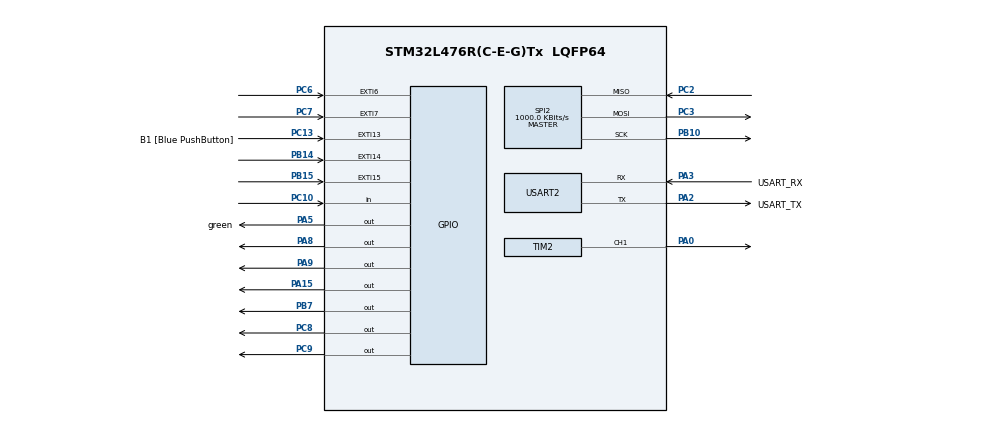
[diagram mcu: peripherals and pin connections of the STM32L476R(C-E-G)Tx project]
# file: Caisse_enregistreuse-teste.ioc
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Mcu.Family=STM32L4
Mcu.Name=STM32L476R(C-E-G)Tx
Mcu.Package=LQFP64
NVIC.PriorityGroup=NVIC_PRIORITYGROUP_4
NVIC.USART2_IRQn=true\:0\:0\:false\:false\:true\:true\:true\:true
PA0.Signal=S_TIM2_CH1
PA13\ (JTMS-SWDIO).GPIO_Label=TMS
PA13\ (JTMS-SWDIO).Mode=Serial_Wire
PA13\ (JTMS-SWDIO).Signal=SYS_JTMS-SWDIO
PA14\ (JTCK-SWCLK).GPIO_Label=TCK
PA14\ (JTCK-SWCLK).Mode=Serial_Wire
PA14\ (JTCK-SWCLK).Signal=SYS_JTCK-SWCLK
PA15\ (JTDI).GPIO_PuPd=GPIO_NOPULL
PA15\ (JTDI).GPIO_Speed=GPIO_SPEED_FREQ_HIGH
PA15\ (JTDI).Signal=GPIO_Output
PA2.GPIO_Label=USART_TX
PA2.GPIO_Mode=GPIO_MODE_AF_PP
PA2.GPIO_PuPd=GPIO_NOPULL
PA2.GPIO_Speed=GPIO_SPEED_FREQ_VERY_HIGH
PA2.Mode=Asynchronous
PA2.Signal=USART2_TX
PA3.GPIO_Label=USART_RX
PA3.GPIO_Mode=GPIO_MODE_AF_PP
PA3.GPIO_PuPd=GPIO_NOPULL
PA3.GPIO_Speed=GPIO_SPEED_FREQ_VERY_HIGH
PA3.Mode=Asynchronous
PA3.Signal=USART2_RX
PA5.GPIO_Label=green
PA5.GPIO_ModeDefaultOutputPP=GPIO_MODE_OUTPUT_PP
PA5.GPIO_PuPd=GPIO_NOPULL
PA5.GPIO_Speed=GPIO_SPEED_FREQ_LOW
PA5.Signal=GPIO_Output
PA8.Signal=GPIO_Output
PA9.Signal=GPIO_Output
PB10.Mode=Full_Duplex_Master
PB10.Signal=SPI2_SCK
PB14.GPIO_ModeDefaultEXTI=GPIO_MODE_IT_FALLING
PB14.GPIO_PuPd=GPIO_PULLUP
PB14.Signal=GPXTI14
PB15.GPIO_ModeDefaultEXTI=GPIO_MODE_IT_FALLING
PB15.GPIO_PuPd=GPIO_PULLUP
PB15.Signal=GPXTI15
PB7.GPIO_Speed=GPIO_SPEED_FREQ_HIGH
PB7.Signal=GPIO_Output
PC10.GPIO_PuPd=GPIO_PULLUP
PC10.Signal=GPIO_Input
PC13.GPIO_Label=B1 [Blue PushButton]
PC13.GPIO_ModeDefaultEXTI=GPIO_MODE_IT_FALLING
PC13.GPIO_PuPd=GPIO_PULLUP
PC13.Signal=GPXTI13
PC14-OSC32_IN\ (PC14).Mode=LSE-External-Oscillator
PC14-OSC32_IN\ (PC14).Signal=RCC_OSC32_IN
PC15-OSC32_OUT\ (PC15).Mode=LSE-External-Oscillator
PC15-OSC32_OUT\ (PC15).Signal=RCC_OSC32_OUT
PC2.Mode=Full_Duplex_Master
PC2.Signal=SPI2_MISO
PC3.Mode=Full_Duplex_Master
PC3.Signal=SPI2_MOSI
PC6.GPIO_ModeDefaultEXTI=GPIO_MODE_IT_FALLING
PC6.GPIO_PuPd=GPIO_PULLUP
PC6.Signal=GPXTI6
PC7.GPIO_ModeDefaultEXTI=GPIO_MODE_IT_FALLING
PC7.GPIO_PuPd=GPIO_PULLUP
PC7.Signal=GPXTI7
PC8.Signal=GPIO_Output
PC9.Signal=GPIO_Output
PH0-OSC_IN\ (PH0).Mode=HSE-External-Oscillator
PH0-OSC_IN\ (PH0).Signal=RCC_OSC_IN
PH1-OSC_OUT\ (PH1).Mode=HSE-External-Oscillator
PH1-OSC_OUT\ (PH1).Signal=RCC_OSC_OUT
ProjectManager.HeapSize=0x200
ProjectManager.StackSize=0x400
ProjectManager.TargetToolchain=STM32CubeIDE
RCC.ADCFreq_Value=64000000
RCC.AHBCLKDivider=RCC_SYSCLK_DIV8
RCC.AHBFreq_Value=8000000
RCC.APB1Freq_Value=8000000
RCC.APB1TimFreq_Value=8000000
RCC.APB2Freq_Value=8000000
RCC.APB2TimFreq_Value=8000000
RCC.CortexFreq_Value=8000000
RCC.HCLKFreq_Value=8000000
RCC.HSE_VALUE=8000000
RCC.HSI_VALUE=16000000
RCC.MSI_VALUE=4000000
RCC.PLLSourceVirtual=RCC_PLLSOURCE_HSI
RCC.SYSCLKFreq_VALUE=64000000
RCC.SYSCLKSource=RCC_SYSCLKSOURCE_PLLCLK
RCC.USBFreq_Value=64000000
RCC.VCOOutputFreq_Value=128000000
SH.S_TIM2_CH1.0=TIM2_CH1,PWM Generation1 CH1
SPI2.BaudRatePrescaler=SPI_BAUDRATEPRESCALER_8
SPI2.CalculateBaudRate=1000.0 KBits/s
SPI2.Direction=SPI_DIRECTION_2LINES
SPI2.Mode=SPI_MODE_MASTER
SPI2.VirtualType=VM_MASTER
USART2.VirtualMode-Asynchronous=VM_ASYNC
VP_TIM2_VS_ControllerModeClock.Mode=Clock Mode
board=NUCLEO-L476RG

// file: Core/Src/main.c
/* USER CODE BEGIN Header */
/**
  ******************************************************************************
  * @file           : main.c
  * @brief          : Main program body
  ******************************************************************************
  * @attention
  *
  * Copyright (c) 2025 STMicroelectronics.
  * All rights reserved.
  *
  * This software is licensed under terms that can be found in the LICENSE file
  * in the root directory of this software component.
  * If no LICENSE file comes with this software, it is provided AS-IS.
  *
  ******************************************************************************
  */
/* USER CODE END Header */
#include "main.h"
#include "spi.h"
#include "tim.h"
#include "usart.h"
#include "gpio.h"

/* USER CODE BEGIN Includes */
#include <stdint.h>
#include "pn532.h"
#include "stdio.h"
#include "string.h"
#include "pn532_stm32f1.h"
/* USER CODE END Includes */

/* USER CODE BEGIN PD */
#define use_HEXADECIMAL
/* USER CODE END PD */

/* USER CODE BEGIN PV */
PN532 pn532;

/* USER CODE END PV */

void SystemClock_Config(void);

/* USER CODE BEGIN 0 */
#ifdef __GNUC__
#define PUTCHAR_PROTOTYPE int __io_putchar(int ch)
#else
#define PUTCHAR_PROTOYPE int fputc(int ch, FILE *f)
#endif

PUTCHAR_PROTOTYPE
{
	HAL_UART_Transmit(&huart2, (uint8_t *)&ch, 1, HAL_MAX_DELAY);
	return ch;
}
/* USER CODE END 0 */

int main(void)
{

  /* USER CODE BEGIN 1 */

	uint8_t buff[255];
	uint8_t uid[MIFARE_UID_MAX_LENGTH];
	int32_t uid_len = 0;
  /* USER CODE END 1 */

  /* MCU Configuration--------------------------------------------------------*/

  /* Reset of all peripherals, Initializes the Flash interface and the Systick. */
  HAL_Init();

  /* Configure the system clock */
  SystemClock_Config();

  /* Initialize all configured peripherals */
  MX_GPIO_Init();
  MX_USART2_UART_Init();
  MX_TIM2_Init();
  MX_SPI2_Init();
  /* USER CODE BEGIN 2 */
//  void SPI_TransmitReceive(uint8_t dataToSend, uint8_t* receivedData)
//  {
//      HAL_GPIO_WritePin(GPIOA, GPIO_PIN_15, GPIO_PIN_RESET); // Activer le PN532 (mettre SS à LOW)
//
//      HAL_SPI_Transmit(&hspi2, &dataToSend, 1, HAL_MAX_DELAY); // Transmettre un octet
//
//      HAL_SPI_Receive(&hspi2, receivedData, 1, HAL_MAX_DELAY);  // Lire la réponse du PN532
//
//      HAL_GPIO_WritePin(GPIOA, GPIO_PIN_15, GPIO_PIN_SET); // Désactiver le PN532 (mettre SS à HIGH)
//  }

  /* USER CODE END 2 */

  /* Infinite loop */
  /* USER CODE BEGIN WHILE */
  while (1)
  {
	  /*HAL_GPIO_WritePin(GPIOC, GPIO_PIN_9, 1);
	  HAL_GPIO_WritePin(GPIOC, GPIO_PIN_8, 1);
	  HAL_GPIO_WritePin(GPIOB, GPIO_PIN_15, 1);
	  HAL_GPIO_WritePin(GPIOB, GPIO_PIN_14, 1);
	  if(flag==1){
		  HAL_GPIO_TogglePin(green_GPIO_Port, green_Pin);
		  flag=0;*/
	   uint8_t testByte[10] = {0xAA, 0x10, 0x20, 0xAA, 0x10, 0x20, 0xAA, 0x10, 0x20, 0xAA}; // Octet à envoyer
	   uint8_t receivedByte = 0;

	    // Envoi et réception via SPI
//	    SPI_TransmitReceive(testByte, &receivedByte);

	    // Vérifier la réponse
	    printf("Octet envoyé: 0x%02X, Octet reçu: 0x%02X\r\n", testByte, receivedByte);

	    if (HAL_GPIO_ReadPin(GPIOC, GPIO_PIN_10) == GPIO_PIN_RESET) {
	        printf("IRQ est à LOW : le PN532 a une donnée prête.\r\n");
	    } else {
	        printf("IRQ est à HIGH : le PN532 ne signale rien.\r\n");
	    }

	    HAL_Delay(1000); // Petite pause pour éviter de surcharger le terminal

	    HAL_GPIO_WritePin(nCS_GPIO_Port, nCS_Pin, RESET);
	    HAL_SPI_Transmit(&hspi2, testByte, 10, 100);
	    HAL_GPIO_WritePin(nCS_GPIO_Port, nCS_Pin, SET);
    /* USER CODE END WHILE */

  }
}

void SystemClock_Config(void)
{
  RCC_OscInitTypeDef RCC_OscInitStruct = {0};
  RCC_ClkInitTypeDef RCC_ClkInitStruct = {0};

  /** Configure the main internal regulator output voltage
  */
  if (HAL_PWREx_ControlVoltageScaling(PWR_REGULATOR_VOLTAGE_SCALE1) != HAL_OK)
  {
    Error_Handler();
  }

  /** Initializes the RCC Oscillators according to the specified parameters
  * in the RCC_OscInitTypeDef structure.
  */
  RCC_OscInitStruct.OscillatorType = RCC_OSCILLATORTYPE_HSI;
  RCC_OscInitStruct.HSIState = RCC_HSI_ON;
  RCC_OscInitStruct.HSICalibrationValue = RCC_HSICALIBRATION_DEFAULT;
  RCC_OscInitStruct.PLL.PLLState = RCC_PLL_ON;
  RCC_OscInitStruct.PLL.PLLSource = RCC_PLLSOURCE_HSI;
  RCC_OscInitStruct.PLL.PLLM = 1;
  RCC_OscInitStruct.PLL.PLLN = 10;
  RCC_OscInitStruct.PLL.PLLP = RCC_PLLP_DIV7;
  RCC_OscInitStruct.PLL.PLLQ = RCC_PLLQ_DIV2;
  RCC_OscInitStruct.PLL.PLLR = RCC_PLLR_DIV2;
  if (HAL_RCC_OscConfig(&RCC_OscInitStruct) != HAL_OK)
  {
    Error_Handler();
  }

  /** Initializes the CPU, AHB and APB buses clocks
  */
  RCC_ClkInitStruct.ClockType = RCC_CLOCKTYPE_HCLK|RCC_CLOCKTYPE_SYSCLK
                              |RCC_CLOCKTYPE_PCLK1|RCC_CLOCKTYPE_PCLK2;
  RCC_ClkInitStruct.SYSCLKSource = RCC_SYSCLKSOURCE_PLLCLK;
  RCC_ClkInitStruct.AHBCLKDivider = RCC_SYSCLK_DIV1;
  RCC_ClkInitStruct.APB1CLKDivider = RCC_HCLK_DIV1;
  RCC_ClkInitStruct.APB2CLKDivider = RCC_HCLK_DIV1;

  if (HAL_RCC_ClockConfig(&RCC_ClkInitStruct, FLASH_LATENCY_4) != HAL_OK)
  {
    Error_Handler();
  }
}

/* USER CODE BEGIN 4 */
void HAL_GPIO_EXTI_Callback(uint16_t GPIO_Pin){
	//flag=1;
}
/* USER CODE END 4 */

void Error_Handler(void)
{
  __disable_irq();
  while (1)
  {
  }
}
